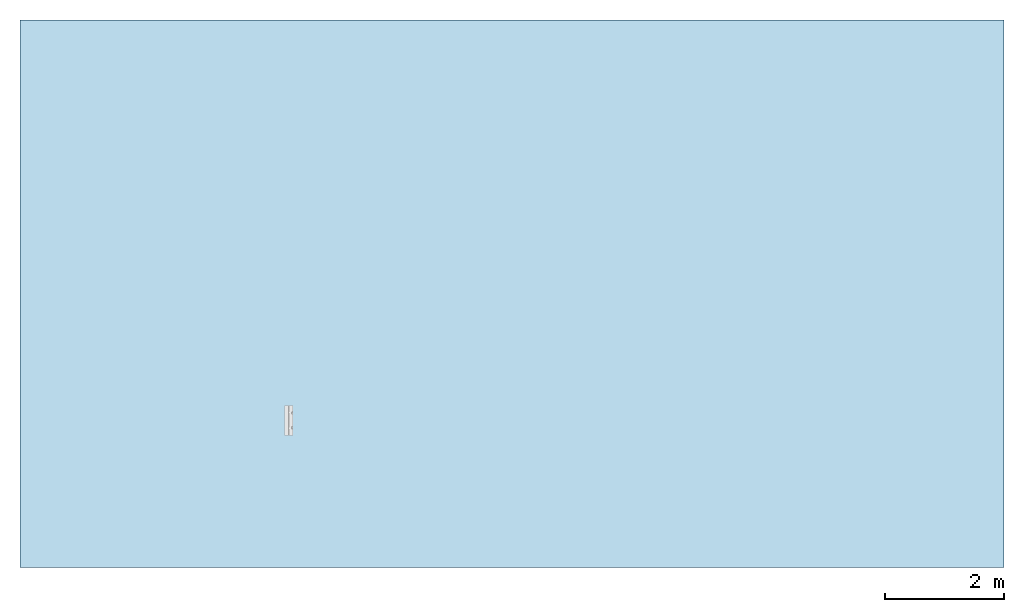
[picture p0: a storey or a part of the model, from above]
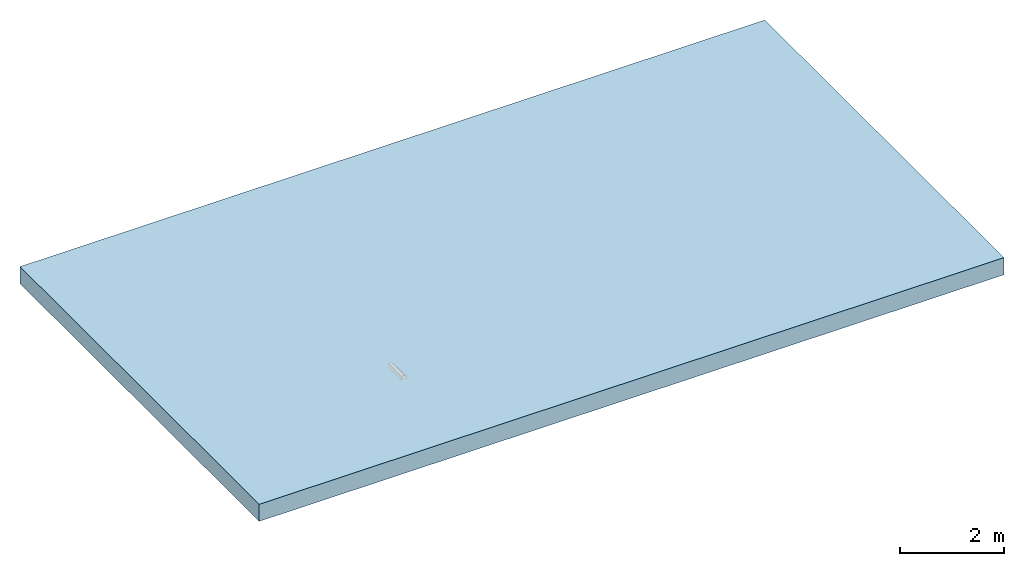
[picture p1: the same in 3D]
Properties of the parts of a building model (IFC2X3)

# File
Description: ViewDefinition [CoordinationView]
File name: 7935 - KDSP280 Channel - 500mm LG.ifc
Time: 2013-09-02T12:28:32
Written by: Autodesk Revit 2013
Made in: 20120221_2030(x64)

# IfcProject, Project Number
LongName: Project Name; Phase: Project Status

# IfcSite, Default
RefLatitude: 42, 21, 30, 344238; RefLongitude: -71, -3, -35, -194702; RefElevation: 0 mm

# IfcBuilding
Pset_BuildingCommon - NumberOfStoreys: 1
Other - Project Status: Project Status; Project Address: ## Street City, State Zip; Project Name: Project Name; Project Number: Project Number; Project Issue Date: Issue Date; Client Name: Owner

# IfcBuildingStorey, Level 1
LongName: Level 1; Elevation: 0 mm
Constraints - Elevation Base: 0; Elevation: 0 mm
Graphics - Symbol at End 2 Default: yes; Color: 0; Line Weight: 1; Symbol at End 1 Default: no; Symbol: M_Level Head - Circle: M_Level Head - Circle; Line Pattern: Center
Identity Data - Building Story: yes; Name: Level 1; Structural: no
Dimensions - Computation Height: 0 mm

# IfcBuildingElementProxy: 7935 - KDSP280 Channel - 500mm LG, Civil-Drainage-Channel-ACO-KerbDrain-SP280:7935 - KDSP280 Channel - 500mm LG:7935 - KDSP280 Channel - 500mm LG:311063
In: Level 1
Material: ACO Polymer Concrete.
Dimensions - Volume: 11622074 mm3; AccessDepth: 0 mm; Access hole: 2 mm; Void Length: 500 mm; Void Depth: -180 mm; Endcap void: 205 mm; Void Width: 150 mm
Constraints - Level: Level: Level 1; Moves With Nearby Elements: no
Phasing - Phase Created: New Construction
Pset_BuildingElementProxyCommon - Reference: 7935 - KDSP280 Channel - 500mm LG
Identity Data - Model: ACO KerbDrain SP280; URL: www.aco.co.uk; Product brochure: http://www.aco.co.uk/download.php?id=120; Model Description: Combined kerb and drainage system; Assembly Code: D2040; e-mail Sales: customersupport@aco.co.uk; Manufacturer: ACO Technologies plc - ACO Water Management Division; Product Page URL: http://www.aco.co.uk/product_detail.php?id=3; e-mail Technical: technical@aco.co.uk; Type Comments: ACO KerbDrain SP280 splayed kerb unit 500mm long; OmniClass Number: 23.70.50.24; Cost: 0; Telephone: +44 (0)1462 816666; Price: POA - contact ACO; Fax: +44 (0)1462 815895; Assembly Description: Rain Water Drainage; Maintenance guidelines: http://www.aco.co.uk/download.php?id=120; Installation guidelines: http://www.aco.co.uk/download.php?id=120; OmniClass Title: Rainwater Removal; Address: ACO Business Park, Hitchin Road, Shefford, Bedfordshire, United Kingdom SG17 5TE; Product Code: 7935
Data - Installation - Concrete Grade: Refer to brochure; Invert Depth: 255mm; Product Standard: BS EN 1433:2002, CE marked, Kitemarked; Connection Pipe O.D: N/A; Channel C.S.A: 0.02m²; Drainage Slot Intake area: 14592mm²/m; Concrete Surround Volume - Load Class A 15 - D 400 - Concrete Pavement: 0.14m³/m; Load Class: A 15 - D 400 A 15 - D 400; Hydraulic Performance: http://www.aco.co.uk/download.php?id=120; Product Weight: 22.2 kg; Concrete Surround Volume - Load Class A 15 - D 400 - Grass or Asphalt Pavement: 0.12m³/m; Product Dimensions: 500mm x 150mm x 280mm (LxWxH); ACO Hydraulic Design Software: http://www.acodesign.co.uk; Drainage Slot Width: 50mm
Construction - Closing end cap: no; perforated centre stone: no; RH drop kerb: no; SP280-500: yes; Centre Stone: no; SP280 - 1000: no; LH transition unit: no; LH drop kerb: no; Access Unit: no; RH transition unit: no; LH inlet/outlet end cap: no; RH inlet/outlet end cap: no
Materials and Finishes - Access Cover/Frame Colour: N/A; Connection Pipe Material: N/A; Access Cover/Frame Finish: N/A; Channel Material: Vienite® Synthetic Resin Concrete; Channel Colour: Grey; End Cap Material: N/A; Access Cover/Frame Material: N/A; End Cap Colour: N/A; Connection Pipe Material Colour: N/A
Other - Revision: 1; CreatedBy: www.aco.co.uk
General - TagNumber: 0.000000; SerialNumber: 0.000000
Green Building Properties - Access Cover/Frame Recycled Material Content: N/A; Channel Recycled Material Content: 20% minimum; Channel Recyclable: Fully recyclable; End Cap Recycled Material Content: N/A; Access Cover/Frame Recyclable: N/A; End Cap Recyclable: N/A

# IfcOpeningElement: Recess
In: Level 1
Dimensions - Perimeter: 51360 mm; Thickness: 400 mm; Area: 151470000 mm2; Volume: 60574500000 mm3
Constraints - Related to Mass: no; Room Bounding: yes; Level: Level: Level 1; Height Offset From Level: 0 mm
Phasing - Phase Created: New Construction
Structural - Enable Analytical Model: no; Structural: no
Materials and Finishes - Structural Material: Plant
Analytical Properties - Absorptance: 0.1; Roughness: 1
Graphics - Coarse Scale Fill Color: 0
Construction - Default Thickness: 400 mm; Function: 0

# IfcSlab: Floor:Generic Floor - 400mm, Floor:Generic Floor - 400mm:193825
In: Level 1
PredefinedType: FLOOR; Material: Plant 400 mm
Dimensions - Perimeter: 51360 mm; Thickness: 400 mm; Area: 151470000 mm2; Volume: 60574500000 mm3
Constraints - Related to Mass: no; Room Bounding: yes; Level: Level: Level 1; Height Offset From Level: 0 mm
Phasing - Phase Created: New Construction
Structural - Enable Analytical Model: no; Structural: no
Pset_SlabCommon - Reference: Generic Floor - 400mm; IsExternal: no; LoadBearing: yes
Materials and Finishes - Structural Material: Plant
Analytical Properties - Absorptance: 0.1; Roughness: 1
Graphics - Coarse Scale Fill Color: 0
Construction - Default Thickness: 400 mm; Function: 0
